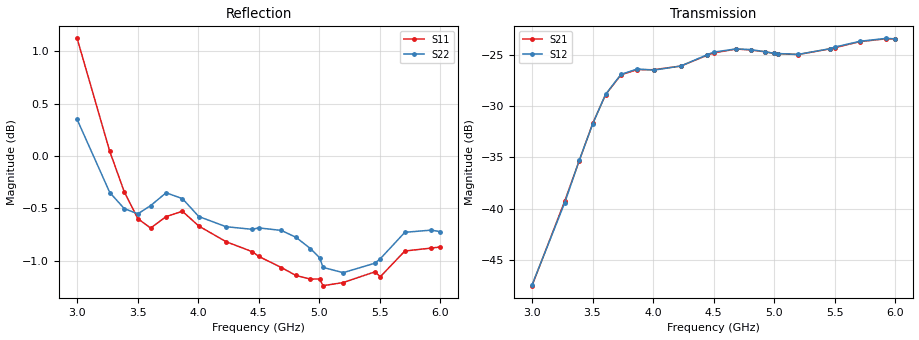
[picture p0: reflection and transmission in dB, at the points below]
!  04/11/2025  15:47:18
! Ref Plane: 0.000 mm
# MHZ S MA R  50
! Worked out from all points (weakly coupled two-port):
!   401 points, 3 GHz to 6 GHz, reference 50 ohm
!   highest |S21| = -23.40 dB at 5.925 GHz (marker M1); lowest = -47.5 dB at 3 GHz (marker M2)
!   lowest |S11| = -1.2 dB at 5.032 GHz (marker M3), VSWR 14.05, Z = 14.8 - j88.1 ohm
!   |S11| at or under -10 dB: nowhere
!   |S22| runs from -1.2 to 0.4 dB; largest |S21 - S12| = 0.0014
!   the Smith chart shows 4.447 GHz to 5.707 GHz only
!   S11 on the Smith chart (normalised r, x): 4.447 GHz: 0.07, +0.58; 4.688 GHz: 0.42, +2.40; 4.928 GHz: 1.07, -3.71; 5.197 GHz: 0.11, -0.77; 5.46 GHz: 0.06, -0.01; 5.707 GHz: 0.08, +0.70
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3000  1.138 -112.7  0.004199 55.5  0.004232 57.4  1.041 -116.8
3270  1.005 179.6  0.01087 -13.0  0.01067 -11.2  0.9606 175.7
3390  0.9612 141.8  0.01713 -49.6  0.0172 -49.6  0.9437 137.4
3502.5  0.9333 99.3  0.02618 -91.2  0.02605 -90.8  0.9384 94.7
3607.5  0.9238 54.7  0.03605 -134.7  0.03616 -134.5  0.9469 50.5
3735  0.9355 -2.1  0.0451 168.7  0.04528 169.6  0.9603 -5.4
3870  0.941 -56.9  0.04778 113.2  0.04816 114.2  0.9542 -59.7
4005  0.9259 -104.4  0.04773 65.8  0.04751 66.4  0.9356 -106.5
4230  0.9101 -174.5  0.04976 -4.7  0.04978 -4.0  0.9252 -176.6
4447.5  0.9001 119.3  0.05618 -71.8  0.05652 -71.1  0.9225 114.8
4500  0.8955 102.8  0.05766 -88.5  0.05819 -87.7  0.924 98.0
4687.5  0.8846 44.3  0.06026 -148.4  0.06037 -147.9  0.9214 36.4
4807.5  0.8769 7.6  0.0596 174.3  0.05988 175.0  0.9145 -2.0
4927.5  0.8734 -28.1  0.05836 139.1  0.05843 139.7  0.9032 -38.3
5002.5  0.8735 -49.4  0.05734 117.8  0.0573 118.4  0.8942 -59.6
5032.5  0.8671 -58.1  0.0572 109.2  0.05728 110.0  0.8847 -68.5
5197.5  0.8701 -104.7  0.05663 64.8  0.05672 65.3  0.8796 -112.7
5460  0.8804 -179.3  0.06035 -6.3  0.06046 -5.7  0.8888 176.7
5505  0.8757 168.5  0.06124 -18.4  0.06166 -17.6  0.8932 164.4
5707.5  0.9008 109.8  0.06548 -76.7  0.06571 -75.7  0.9195 107.3
5925  0.9037 48.6  0.06763 -140.4  0.06794 -139.7  0.9217 44.7
6000  0.9048 26.9  0.06724 -162.8  0.06757 -162.1  0.9202 22.6
